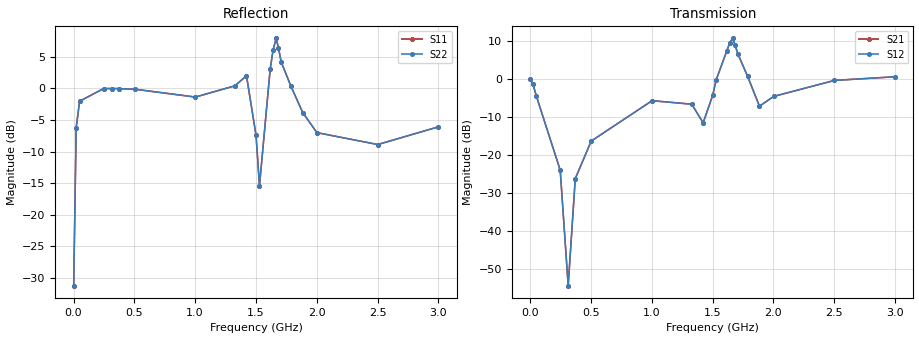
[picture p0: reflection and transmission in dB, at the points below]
!s-Parameter Generated by FASTRON Sdn. Bhd.
!FASTRON P/N : MICC-R47X
!Keysight Technologies,E4991B,MY54100416,A.01.15
!Date: Fri Aug 21 13:29:38 2026
!Version  : Rev00 Fri Aug 21 13:29:38 2026
!Data & Calibration Information:
!PortZ  Port1:50+j0  Port2:50+j0
!When reading, reference impedance value at option line is always used.
! Remarks : This data is being provided solely for informational purposes.
!Freq	S11	S21	S12	S22
# Hz S dB R 50
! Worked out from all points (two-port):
!   1601 points, 1 MHz to 3 GHz, reference 50 ohm
!   highest |S21| = 10.69 dB at 1.665 GHz (marker M1); lowest = -54.5 dB at 312.1 MHz (marker M2)
!   |S21| within 3 dB of the highest: 1.62 GHz to 1.694 GHz (74.28 MHz wide, 4.48 % of centre)
!   lowest |S11| = -31.2 dB at 1 MHz (marker M3), VSWR 1.06, Z = 50.3 + j2.74 ohm
!   |S11| at or under -10 dB: start of sweep to 12.78 MHz; 1.507 GHz to 1.541 GHz (33.89 MHz wide, 2.22 % of centre)
!   |S22| runs from -31.2 to 7.9 dB; largest |S21 - S12| = 0
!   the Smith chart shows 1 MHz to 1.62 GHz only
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1000000  -31.22 83.1  -0.03 -1.6  -0.03 -1.6  -31.22 83.1
2.161812e7  -6.21 59.4  -1.30 -29.3  -1.30 -29.3  -6.21 59.4
4.973375e7  -2.03 36.8  -4.45 -52.3  -4.45 -52.3  -2.03 36.8
2.465431e8  -0.03 3.6  -24.05 -84.8  -24.05 -84.8  -0.03 3.6
3.121462e8  -0.02 0.0  -54.50 -1.1  -54.50 -1.1  -0.02 0.0
3.702519e8  -0.03 -2.8  -26.29 85.0  -26.29 85.0  -0.03 -2.8
5.014581e8  -0.12 -8.7  -16.38 80.4  -16.38 80.4  -0.12 -8.7
1.001916e9  -1.37 -31.1  -5.74 58.6  -5.74 58.6  -1.37 -31.1
1.328058e9  0.42 -26.0  -6.66 83.0  -6.66 83.0  0.42 -26.0
1.421776e9  2.01 -2.3  -11.58 168.7  -11.58 168.7  2.01 -2.3
1.5005e9  -7.44 17.5  -4.31 -12.1  -4.31 -12.1  -7.44 17.5
1.528616e9  -15.42 -74.1  -0.29 9.7  -0.29 9.7  -15.42 -74.1
1.616711e9  3.07 -151.7  7.43 16.7  7.43 16.7  3.07 -151.7
1.641078e9  6.11 -173.5  9.59 4.3  9.59 4.3  6.11 -173.5
1.665445e9  7.92 155.6  10.69 -17.4  10.69 -17.4  7.92 155.6
1.684189e9  6.47 124.0  8.92 -38.7  8.92 -38.7  6.47 124.0
1.706681e9  4.21 107.7  6.65 -46.0  6.65 -46.0  4.21 107.7
1.787279e9  0.34 64.0  0.68 -59.8  0.68 -59.8  0.34 64.0
1.884747e9  -3.84 18.1  -7.19 -27.1  -7.19 -27.1  -3.84 18.1
2.000958e9  -7.00 -16.9  -4.62 12.8  -4.62 12.8  -7.00 -16.9
2.501416e9  -8.88 -72.5  -0.39 21.0  -0.39 21.0  -8.88 -72.5
3e9  -6.08 -83.8  0.57 27.5  0.57 27.5  -6.08 -83.8
